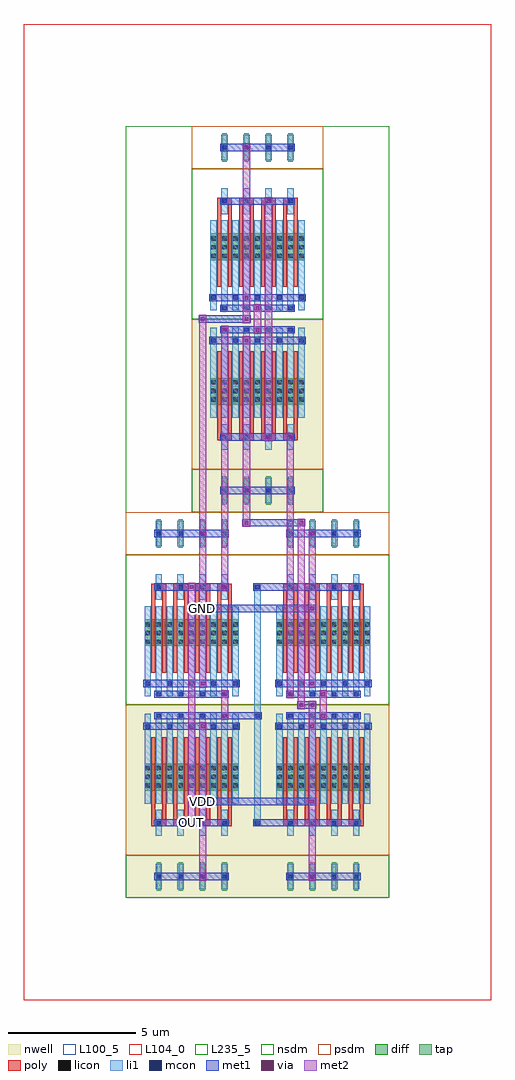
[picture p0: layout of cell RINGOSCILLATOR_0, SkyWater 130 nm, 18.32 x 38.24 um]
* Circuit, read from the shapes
.subckt RINGOSCILLATOR_0 GND OUT VDD
XM1 n1 OUT GND GND sky130_fd_pr__nfet_01v8 w=1.05 l=0.15 m=8
XM2 OUT n2 GND GND sky130_fd_pr__nfet_01v8 w=1.05 l=0.15 m=8
XM3 n2 n1 GND GND sky130_fd_pr__nfet_01v8 w=1.05 l=0.15 m=8
XM4 n1 OUT VDD VDD sky130_fd_pr__pfet_01v8 w=1.05 l=0.15 m=8
XM5 OUT n2 VDD VDD sky130_fd_pr__pfet_01v8 w=1.05 l=0.15 m=8
XM6 n2 n1 VDD VDD sky130_fd_pr__pfet_01v8 w=1.05 l=0.15 m=8
.ends

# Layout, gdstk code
from math import pi, radians
import gdstk
lib = gdstk.Library(unit=1e-6, precision=1e-09)
def R(c, l, rs):  # rectangles x0, y0, x1, y1
    for r in rs: c.add(gdstk.rectangle(r[:2], r[2:], *l))
def A(c, l, x, y, w, h, nx, ny, dx, dy):  # array of equal rectangles
    R(c, l, [(x+i*dx, y+j*dy, x+i*dx+w, y+j*dy+h) for i in range(nx) for j in range(ny)])
def P(c, l, *ps):  # polygons
    for p in ps: c.add(gdstk.Polygon(p, *l))
nwell = (64, 20)
diff = (65, 20)
tap = (65, 44)
poly = (66, 20)
licon = (66, 44)
li1 = (67, 20)
mcon = (67, 44)
met1 = (68, 20)
via = (68, 44)
met2 = (69, 20)
nsdm = (93, 44)
psdm = (94, 20)
L100_5 = (100, 5)
L104_0 = (104, 0)
L235_5 = (235, 5)

nmos_s_73579002_x4_y1_16 = lib.new_cell('NMOS_S_73579002_X4_Y1_1678723525_1678723529')
R(nmos_s_73579002_x4_y1_16, diff, [(0.735,2.31,4.425,3.36)])
A(nmos_s_73579002_x4_y1_16, tap, 1.205, 6.16, 0.17, 1.12, 4, 1, 0.86, 0)
A(nmos_s_73579002_x4_y1_16, poly, 1, 1.26, 0.15, 3.36, 8, 1, 0.43, 0)
A(nmos_s_73579002_x4_y1_16, poly, 1, 4.485, 0.58, 0.27, 4, 1, 0.86, 0)
A(nmos_s_73579002_x4_y1_16, licon, 0.775, 2.39, 0.17, 0.17, 3, 3, 0.43, 0.34)
A(nmos_s_73579002_x4_y1_16, licon, 1.635, 2.39, 0.17, 0.17, 3, 3, 0.43, 0.34)
A(nmos_s_73579002_x4_y1_16, licon, 2.495, 2.39, 0.17, 0.17, 3, 3, 0.43, 0.34)
A(nmos_s_73579002_x4_y1_16, licon, 3.355, 2.39, 0.17, 0.17, 3, 3, 0.43, 0.34)
A(nmos_s_73579002_x4_y1_16, licon, 1.205, 4.535, 0.17, 0.17, 4, 2, 0.86, 2.1)
A(nmos_s_73579002_x4_y1_16, li1, 0.735, 0.335, 0.25, 3.53, 9, 1, 0.43, 0)
A(nmos_s_73579002_x4_y1_16, li1, 1.165, 4.115, 0.25, 1.01, 4, 2, 0.86, 2.1)
A(nmos_s_73579002_x4_y1_16, mcon, 1.205, 0.335, 0.17, 0.17, 4, 2, 0.86, 4.2)
A(nmos_s_73579002_x4_y1_16, mcon, 0.775, 0.755, 0.17, 0.17, 5, 1, 0.86, 0)
A(nmos_s_73579002_x4_y1_16, mcon, 1.205, 6.635, 0.17, 0.17, 4, 1, 0.86, 0)
R(nmos_s_73579002_x4_y1_16, met1, [(1.12,0.28,4.04,0.56), (0.69,0.7,4.47,0.98), (1.12,4.48,4.04,4.76), (1.12,6.58,4.04,6.86)])
R(nmos_s_73579002_x4_y1_16, via, [(2.935,0.765,3.085,0.915), (2.935,6.645,3.085,6.795)])
R(nmos_s_73579002_x4_y1_16, met2, [(2.87,0.68,3.15,6.88)])
R(nmos_s_73579002_x4_y1_16, nsdm, [(0,0,5.16,5.88)])
R(nmos_s_73579002_x4_y1_16, psdm, [(0,5.88,5.16,7.56)])
R(nmos_s_73579002_x4_y1_16, L100_5, [(0,0,5.16,7.56)])

pmos_s_34365194_x4_y1_16 = lib.new_cell('PMOS_S_34365194_X4_Y1_1678723526_1678723529')
R(pmos_s_34365194_x4_y1_16, nwell, [(0,0,5.16,7.56)])
R(pmos_s_34365194_x4_y1_16, diff, [(0.735,2.31,4.425,3.36)])
A(pmos_s_34365194_x4_y1_16, tap, 1.205, 6.16, 0.17, 1.12, 4, 1, 0.86, 0)
A(pmos_s_34365194_x4_y1_16, poly, 1, 1.26, 0.15, 3.36, 8, 1, 0.43, 0)
A(pmos_s_34365194_x4_y1_16, poly, 1, 4.485, 0.58, 0.27, 4, 1, 0.86, 0)
A(pmos_s_34365194_x4_y1_16, licon, 0.775, 2.39, 0.17, 0.17, 3, 3, 0.43, 0.34)
A(pmos_s_34365194_x4_y1_16, licon, 1.635, 2.39, 0.17, 0.17, 3, 3, 0.43, 0.34)
A(pmos_s_34365194_x4_y1_16, licon, 2.495, 2.39, 0.17, 0.17, 3, 3, 0.43, 0.34)
A(pmos_s_34365194_x4_y1_16, licon, 3.355, 2.39, 0.17, 0.17, 3, 3, 0.43, 0.34)
A(pmos_s_34365194_x4_y1_16, licon, 1.205, 4.535, 0.17, 0.17, 4, 2, 0.86, 2.1)
A(pmos_s_34365194_x4_y1_16, li1, 0.735, 0.335, 0.25, 3.53, 9, 1, 0.43, 0)
A(pmos_s_34365194_x4_y1_16, li1, 1.165, 4.115, 0.25, 1.01, 4, 2, 0.86, 2.1)
A(pmos_s_34365194_x4_y1_16, mcon, 1.205, 0.335, 0.17, 0.17, 4, 2, 0.86, 4.2)
A(pmos_s_34365194_x4_y1_16, mcon, 0.775, 0.755, 0.17, 0.17, 5, 1, 0.86, 0)
A(pmos_s_34365194_x4_y1_16, mcon, 1.205, 6.635, 0.17, 0.17, 4, 1, 0.86, 0)
R(pmos_s_34365194_x4_y1_16, met1, [(1.12,0.28,4.04,0.56), (0.69,0.7,4.47,0.98), (1.12,4.48,4.04,4.76), (1.12,6.58,4.04,6.86)])
R(pmos_s_34365194_x4_y1_16, via, [(2.935,0.765,3.085,0.915), (2.935,6.645,3.085,6.795)])
R(pmos_s_34365194_x4_y1_16, met2, [(2.87,0.68,3.15,6.88)])
R(pmos_s_34365194_x4_y1_16, nsdm, [(0,5.88,5.16,7.56)])
R(pmos_s_34365194_x4_y1_16, psdm, [(0,0,5.16,5.88)])
R(pmos_s_34365194_x4_y1_16, L100_5, [(0,0,5.16,7.56)])

stage2_inv_3267744_0_0_1 = lib.new_cell('STAGE2_INV_3267744_0_0_1678723529')
R(stage2_inv_3267744_0_0_1, li1, [(5.035,2.855,5.285,3.025), (5.035,2.855,5.285,3.025), (5.035,2.855,5.285,3.025), (5.035,2.855,5.285,3.025), (5.035,2.94,5.285,7.14), (5.035,7.055,5.285,7.225), (5.035,7.055,5.285,7.225), (5.035,7.055,5.285,7.225), (5.035,7.055,5.285,7.225), (5.035,7.14,5.285,12.18), (5.035,12.095,5.285,12.265), (5.035,12.095,5.285,12.265)])
R(stage2_inv_3267744_0_0_1, mcon, [(5.075,2.855,5.245,3.025), (5.075,2.855,5.245,3.025), (5.075,2.855,5.245,3.025), (5.075,2.855,5.245,3.025), (5.075,7.055,5.245,7.225), (5.075,7.055,5.245,7.225), (5.075,7.055,5.245,7.225), (5.075,7.055,5.245,7.225), (5.075,12.095,5.245,12.265), (5.075,12.095,5.245,12.265)])
R(stage2_inv_3267744_0_0_1, met1, [(2.42,2.8,2.74,3.08), (2.42,2.8,2.74,3.08), (4.99,2.8,5.33,3.08), (4.99,2.8,5.33,3.08), (4.99,2.8,5.33,3.08), (4.99,2.8,5.33,3.08), (5.16,2.8,6.45,3.08), (2.85,3.64,3.17,3.92), (2.85,3.64,3.17,3.92), (3.01,3.64,7.31,3.92), (7.15,3.64,7.47,3.92), (7.15,3.64,7.47,3.92), (3.71,7,4.03,7.28), (3.71,7,4.03,7.28), (3.71,7,4.03,7.28), (3.71,7,4.03,7.28), (3.71,7,4.03,7.28), (3.71,7,4.03,7.28), (3.87,7,5.16,7.28), (4.99,7,5.33,7.28), (4.99,7,5.33,7.28), (4.99,7,5.33,7.28), (4.99,7,5.33,7.28), (7.58,7,7.9,7.28), (7.58,7,7.9,7.28), (3.71,7.84,4.03,8.12), (3.71,7.84,4.03,8.12), (3.71,7.84,4.03,8.12), (3.71,7.84,4.03,8.12), (3.71,7.84,4.03,8.12), (3.71,7.84,4.03,8.12), (7.58,7.84,7.9,8.12), (7.58,7.84,7.9,8.12), (2.85,11.2,3.17,11.48), (2.85,11.2,3.17,11.48), (3.01,11.2,7.31,11.48), (7.15,11.2,7.47,11.48), (7.15,11.2,7.47,11.48), (2.42,12.04,2.74,12.32), (2.42,12.04,2.74,12.32), (4.99,12.04,5.33,12.32), (4.99,12.04,5.33,12.32), (5.16,12.04,6.45,12.32)])
P(stage2_inv_3267744_0_0_1, met1, [(0,0),(0,0),(0,0),(0,0)],
  [(0,0),(0,0),(0,0),(0,0)],
  [(0,0),(0,0),(0,0),(0,0)],
  [(0,0),(0,0),(0,0),(0,0)],
  [(0,0),(0,0),(0,0),(0,0)],
  [(0,0),(0,0),(0,0),(0,0)],
  [(0,0),(0,0),(0,0),(0,0)],
  [(0,0),(0,0),(0,0),(0,0)])
R(stage2_inv_3267744_0_0_1, via, [(2.505,2.865,2.655,3.015), (2.505,2.865,2.655,3.015), (2.935,3.705,3.085,3.855), (2.935,3.705,3.085,3.855), (7.235,3.705,7.385,3.855), (7.235,3.705,7.385,3.855), (3.795,7.065,3.945,7.215), (3.795,7.065,3.945,7.215), (3.795,7.065,3.945,7.215), (3.795,7.065,3.945,7.215), (3.795,7.065,3.945,7.215), (3.795,7.065,3.945,7.215), (7.665,7.065,7.815,7.215), (7.665,7.065,7.815,7.215), (3.795,7.905,3.945,8.055), (3.795,7.905,3.945,8.055), (3.795,7.905,3.945,8.055), (3.795,7.905,3.945,8.055), (3.795,7.905,3.945,8.055), (3.795,7.905,3.945,8.055), (7.665,7.905,7.815,8.055), (7.665,7.905,7.815,8.055), (2.935,11.265,3.085,11.415), (2.935,11.265,3.085,11.415), (7.235,11.265,7.385,11.415), (7.235,11.265,7.385,11.415), (2.505,12.105,2.655,12.255), (2.505,12.105,2.655,12.255)])
R(stage2_inv_3267744_0_0_1, met2, [(2.44,2.78,2.72,3.1), (2.44,2.78,2.72,3.1), (2.44,2.94,2.72,12.18), (2.87,3.62,3.15,3.94), (2.87,3.62,3.15,3.94), (7.17,3.62,7.45,3.94), (7.17,3.62,7.45,3.94), (3.73,6.98,4.01,7.3), (3.73,6.98,4.01,7.3), (3.73,6.98,4.01,7.3), (3.73,6.98,4.01,7.3), (3.73,6.98,4.01,7.3), (3.73,6.98,4.01,7.3), (7.6,6.98,7.88,7.3), (7.6,6.98,7.88,7.3), (3.73,7.14,4.01,7.98), (7.6,7.14,7.88,7.98), (3.73,7.82,4.01,8.14), (3.73,7.82,4.01,8.14), (3.73,7.82,4.01,8.14), (3.73,7.82,4.01,8.14), (3.73,7.82,4.01,8.14), (3.73,7.82,4.01,8.14), (7.6,7.82,7.88,8.14), (7.6,7.82,7.88,8.14), (2.87,11.18,3.15,11.5), (2.87,11.18,3.15,11.5), (7.17,11.18,7.45,11.5), (7.17,11.18,7.45,11.5), (2.44,12.02,2.72,12.34), (2.44,12.02,2.72,12.34)])
P(stage2_inv_3267744_0_0_1, met2, [(0,0),(0,0),(0,0),(0,0)],
  [(0,0),(0,0),(0,0),(0,0)],
  [(0,0),(0,0),(0,0),(0,0)],
  [(0,0),(0,0),(0,0),(0,0)])
R(stage2_inv_3267744_0_0_1, L235_5, [(0,0,10.32,15.12)])
stage2_inv_3267744_0_0_1.add(gdstk.Reference(nmos_s_73579002_x4_y1_16, (0,7.56)))
stage2_inv_3267744_0_0_1.add(gdstk.Reference(nmos_s_73579002_x4_y1_16, (10.32,7.56), rotation=pi, x_reflection=True))
stage2_inv_3267744_0_0_1.add(gdstk.Reference(pmos_s_34365194_x4_y1_16, (0,7.56), x_reflection=True))
stage2_inv_3267744_0_0_1.add(gdstk.Reference(pmos_s_34365194_x4_y1_16, (10.32,7.56), rotation=pi))

c_nmos_s_73579002_x4_y1_16 = lib.new_cell('NMOS_S_73579002_X4_Y1_1678723526_1678723528')
R(c_nmos_s_73579002_x4_y1_16, diff, [(0.735,2.31,4.425,3.36)])
A(c_nmos_s_73579002_x4_y1_16, tap, 1.205, 6.16, 0.17, 1.12, 4, 1, 0.86, 0)
A(c_nmos_s_73579002_x4_y1_16, poly, 1, 1.26, 0.15, 3.36, 8, 1, 0.43, 0)
A(c_nmos_s_73579002_x4_y1_16, poly, 1, 4.485, 0.58, 0.27, 4, 1, 0.86, 0)
A(c_nmos_s_73579002_x4_y1_16, licon, 0.775, 2.39, 0.17, 0.17, 3, 3, 0.43, 0.34)
A(c_nmos_s_73579002_x4_y1_16, licon, 1.635, 2.39, 0.17, 0.17, 3, 3, 0.43, 0.34)
A(c_nmos_s_73579002_x4_y1_16, licon, 2.495, 2.39, 0.17, 0.17, 3, 3, 0.43, 0.34)
A(c_nmos_s_73579002_x4_y1_16, licon, 3.355, 2.39, 0.17, 0.17, 3, 3, 0.43, 0.34)
A(c_nmos_s_73579002_x4_y1_16, licon, 1.205, 4.535, 0.17, 0.17, 4, 2, 0.86, 2.1)
A(c_nmos_s_73579002_x4_y1_16, li1, 0.735, 0.335, 0.25, 3.53, 9, 1, 0.43, 0)
A(c_nmos_s_73579002_x4_y1_16, li1, 1.165, 4.115, 0.25, 1.01, 4, 2, 0.86, 2.1)
A(c_nmos_s_73579002_x4_y1_16, mcon, 1.205, 0.335, 0.17, 0.17, 4, 2, 0.86, 4.2)
A(c_nmos_s_73579002_x4_y1_16, mcon, 0.775, 0.755, 0.17, 0.17, 5, 1, 0.86, 0)
A(c_nmos_s_73579002_x4_y1_16, mcon, 1.205, 6.635, 0.17, 0.17, 4, 1, 0.86, 0)
R(c_nmos_s_73579002_x4_y1_16, met1, [(1.12,0.28,4.04,0.56), (0.69,0.7,4.47,0.98), (1.12,4.48,4.04,4.76), (1.12,6.58,4.04,6.86)])
R(c_nmos_s_73579002_x4_y1_16, via, [(2.935,0.765,3.085,0.915), (2.935,6.645,3.085,6.795)])
R(c_nmos_s_73579002_x4_y1_16, met2, [(2.87,0.68,3.15,6.88)])
R(c_nmos_s_73579002_x4_y1_16, nsdm, [(0,0,5.16,5.88)])
R(c_nmos_s_73579002_x4_y1_16, psdm, [(0,5.88,5.16,7.56)])
R(c_nmos_s_73579002_x4_y1_16, L100_5, [(0,0,5.16,7.56)])

c_pmos_s_34365194_x4_y1_16 = lib.new_cell('PMOS_S_34365194_X4_Y1_1678723527_1678723528')
R(c_pmos_s_34365194_x4_y1_16, nwell, [(0,0,5.16,7.56)])
R(c_pmos_s_34365194_x4_y1_16, diff, [(0.735,2.31,4.425,3.36)])
A(c_pmos_s_34365194_x4_y1_16, tap, 1.205, 6.16, 0.17, 1.12, 4, 1, 0.86, 0)
A(c_pmos_s_34365194_x4_y1_16, poly, 1, 1.26, 0.15, 3.36, 8, 1, 0.43, 0)
A(c_pmos_s_34365194_x4_y1_16, poly, 1, 4.485, 0.58, 0.27, 4, 1, 0.86, 0)
A(c_pmos_s_34365194_x4_y1_16, licon, 0.775, 2.39, 0.17, 0.17, 3, 3, 0.43, 0.34)
A(c_pmos_s_34365194_x4_y1_16, licon, 1.635, 2.39, 0.17, 0.17, 3, 3, 0.43, 0.34)
A(c_pmos_s_34365194_x4_y1_16, licon, 2.495, 2.39, 0.17, 0.17, 3, 3, 0.43, 0.34)
A(c_pmos_s_34365194_x4_y1_16, licon, 3.355, 2.39, 0.17, 0.17, 3, 3, 0.43, 0.34)
A(c_pmos_s_34365194_x4_y1_16, licon, 1.205, 4.535, 0.17, 0.17, 4, 2, 0.86, 2.1)
A(c_pmos_s_34365194_x4_y1_16, li1, 0.735, 0.335, 0.25, 3.53, 9, 1, 0.43, 0)
A(c_pmos_s_34365194_x4_y1_16, li1, 1.165, 4.115, 0.25, 1.01, 4, 2, 0.86, 2.1)
A(c_pmos_s_34365194_x4_y1_16, mcon, 1.205, 0.335, 0.17, 0.17, 4, 2, 0.86, 4.2)
A(c_pmos_s_34365194_x4_y1_16, mcon, 0.775, 0.755, 0.17, 0.17, 5, 1, 0.86, 0)
A(c_pmos_s_34365194_x4_y1_16, mcon, 1.205, 6.635, 0.17, 0.17, 4, 1, 0.86, 0)
R(c_pmos_s_34365194_x4_y1_16, met1, [(1.12,0.28,4.04,0.56), (0.69,0.7,4.47,0.98), (1.12,4.48,4.04,4.76), (1.12,6.58,4.04,6.86)])
R(c_pmos_s_34365194_x4_y1_16, via, [(2.935,0.765,3.085,0.915), (2.935,6.645,3.085,6.795)])
R(c_pmos_s_34365194_x4_y1_16, met2, [(2.87,0.68,3.15,6.88)])
R(c_pmos_s_34365194_x4_y1_16, nsdm, [(0,5.88,5.16,7.56)])
R(c_pmos_s_34365194_x4_y1_16, psdm, [(0,0,5.16,5.88)])
R(c_pmos_s_34365194_x4_y1_16, L100_5, [(0,0,5.16,7.56)])

inv_97647246_0_0_1678723 = lib.new_cell('INV_97647246_0_0_1678723528')
R(inv_97647246_0_0_1678723, met1, [(2.85,2.8,3.17,3.08), (2.85,2.8,3.17,3.08), (2.42,7,2.74,7.28), (2.42,7,2.74,7.28), (2.42,7.84,2.74,8.12), (2.42,7.84,2.74,8.12), (2.85,12.04,3.17,12.32), (2.85,12.04,3.17,12.32)])
P(inv_97647246_0_0_1678723, met1, [(0,0),(0,0),(0,0),(0,0)],
  [(0,0),(0,0),(0,0),(0,0)],
  [(0,0),(0,0),(0,0),(0,0)],
  [(0,0),(0,0),(0,0),(0,0)])
R(inv_97647246_0_0_1678723, via, [(2.935,2.865,3.085,3.015), (2.935,2.865,3.085,3.015), (2.505,7.065,2.655,7.215), (2.505,7.065,2.655,7.215), (2.505,7.905,2.655,8.055), (2.505,7.905,2.655,8.055), (2.935,12.105,3.085,12.255), (2.935,12.105,3.085,12.255)])
R(inv_97647246_0_0_1678723, met2, [(2.87,2.78,3.15,3.1), (2.87,2.78,3.15,3.1), (2.87,2.94,3.15,12.18), (2.44,6.98,2.72,7.3), (2.44,6.98,2.72,7.3), (2.44,7.14,2.72,7.98), (2.44,7.82,2.72,8.14), (2.44,7.82,2.72,8.14), (2.87,12.02,3.15,12.34), (2.87,12.02,3.15,12.34)])
P(inv_97647246_0_0_1678723, met2, [(0,0),(0,0),(0,0),(0,0)],
  [(0,0),(0,0),(0,0),(0,0)])
R(inv_97647246_0_0_1678723, L235_5, [(0,0,5.16,15.12)])
inv_97647246_0_0_1678723.add(gdstk.Reference(c_nmos_s_73579002_x4_y1_16, (5.16,7.56), rotation=pi))
inv_97647246_0_0_1678723.add(gdstk.Reference(c_pmos_s_34365194_x4_y1_16, (5.16,7.56), rotation=pi, x_reflection=True))

ringoscillator_0 = lib.new_cell('RINGOSCILLATOR_0')
R(ringoscillator_0, met1, [(6.72,7.42,7.04,7.7), (6.72,7.42,7.04,7.7), (6.88,7.42,7.31,7.7), (7.15,7.42,7.47,7.7), (7.15,7.42,7.47,7.7), (6.29,7.84,6.61,8.12), (6.29,7.84,6.61,8.12), (3.71,12.04,4.03,12.32), (3.71,12.04,4.03,12.32), (4.57,14.56,4.89,14.84), (4.57,14.56,4.89,14.84), (4.73,14.56,6.88,14.84), (6.72,14.56,7.04,14.84), (6.72,14.56,7.04,14.84), (6.29,17.92,6.61,18.2), (6.29,17.92,6.61,18.2), (3.71,22.12,4.03,22.4), (3.71,22.12,4.03,22.4), (2.85,22.54,3.17,22.82), (2.85,22.54,3.17,22.82), (3.01,22.54,4.73,22.82), (4.57,22.54,4.89,22.82), (4.57,22.54,4.89,22.82)])
P(ringoscillator_0, met1, [(0,0),(0,0),(0,0),(0,0)],
  [(0,0),(0,0),(0,0),(0,0)],
  [(0,0),(0,0),(0,0),(0,0)],
  [(0,0),(0,0),(0,0),(0,0)],
  [(0,0),(0,0),(0,0),(0,0)],
  [(0,0),(0,0),(0,0),(0,0)],
  [(0,0),(0,0),(0,0),(0,0)],
  [(0,0),(0,0),(0,0),(0,0)],
  [(0,0),(0,0),(0,0),(0,0)],
  [(0,0),(0,0),(0,0),(0,0)],
  [(0,0),(0,0),(0,0),(0,0)],
  [(0,0),(0,0),(0,0),(0,0)],
  [(0,0),(0,0),(0,0),(0,0)],
  [(0,0),(0,0),(0,0),(0,0)],
  [(0,0),(0,0),(0,0),(0,0)],
  [(0,0),(0,0),(0,0),(0,0)],
  [(0,0),(0,0),(0,0),(0,0)],
  [(0,0),(0,0),(0,0),(0,0)],
  [(0,0),(0,0),(0,0),(0,0)])
R(ringoscillator_0, via, [(6.805,7.485,6.955,7.635), (6.805,7.485,6.955,7.635), (7.235,7.485,7.385,7.635), (7.235,7.485,7.385,7.635), (6.375,7.905,6.525,8.055), (6.375,7.905,6.525,8.055), (3.795,12.105,3.945,12.255), (3.795,12.105,3.945,12.255), (4.655,14.625,4.805,14.775), (4.655,14.625,4.805,14.775), (6.805,14.625,6.955,14.775), (6.805,14.625,6.955,14.775), (6.375,17.985,6.525,18.135), (6.375,17.985,6.525,18.135), (3.795,22.185,3.945,22.335), (3.795,22.185,3.945,22.335), (2.935,22.605,3.085,22.755), (2.935,22.605,3.085,22.755), (4.655,22.605,4.805,22.755), (4.655,22.605,4.805,22.755)])
R(ringoscillator_0, met2, [(7.17,6.72,7.45,7.56), (6.74,7.4,7.02,7.72), (6.74,7.4,7.02,7.72), (7.17,7.4,7.45,7.72), (7.17,7.4,7.45,7.72), (6.74,7.56,7.02,14.7), (6.31,7.82,6.59,8.14), (6.31,7.82,6.59,8.14), (6.31,7.98,6.59,18.06), (3.73,12.02,4.01,12.34), (3.73,12.02,4.01,12.34), (3.73,12.18,4.01,22.26), (2.87,14.28,3.15,22.68), (4.59,14.54,4.87,14.86), (4.59,14.54,4.87,14.86), (6.74,14.54,7.02,14.86), (6.74,14.54,7.02,14.86), (4.59,14.7,4.87,15.96), (6.31,17.9,6.59,18.22), (6.31,17.9,6.59,18.22), (3.73,22.1,4.01,22.42), (3.73,22.1,4.01,22.42), (2.87,22.52,3.15,22.84), (2.87,22.52,3.15,22.84), (4.59,22.52,4.87,22.84), (4.59,22.52,4.87,22.84), (4.59,22.68,4.87,23.52)])
P(ringoscillator_0, met2, [(0,0),(0,0),(0,0),(0,0)],
  [(0,0),(0,0),(0,0),(0,0)],
  [(0,0),(0,0),(0,0),(0,0)],
  [(0,0),(0,0),(0,0),(0,0)],
  [(0,0),(0,0),(0,0),(0,0)],
  [(0,0),(0,0),(0,0),(0,0)],
  [(0,0),(0,0),(0,0),(0,0)],
  [(0,0),(0,0),(0,0),(0,0)],
  [(0,0),(0,0),(0,0),(0,0)],
  [(0,0),(0,0),(0,0),(0,0)],
  [(0,0),(0,0),(0,0),(0,0)],
  [(0,0),(0,0),(0,0),(0,0)],
  [(0,0),(0,0),(0,0),(0,0)],
  [(0,0),(0,0),(0,0),(0,0)],
  [(0,0),(0,0),(0,0),(0,0)],
  [(0,0),(0,0),(0,0),(0,0)])
R(ringoscillator_0, L104_0, [(-4,-4,14.32,34.24)])
R(ringoscillator_0, L235_5, [(0,0,10.32,30.24)])
ringoscillator_0.add(gdstk.Reference(stage2_inv_3267744_0_0_1, (0,0)))
ringoscillator_0.add(gdstk.Reference(inv_97647246_0_0_1678723, (2.58,30.24), x_reflection=True))
ringoscillator_0.add(gdstk.Label('GND', (3.01,11.34), layer=69, texttype=5))
ringoscillator_0.add(gdstk.Label('VDD', (3.01,3.78), layer=69, texttype=5))
ringoscillator_0.add(gdstk.Label('OUT', (2.58,2.94), layer=68, texttype=5))

lib.write_gds('RINGOSCILLATOR_0.gds')
